VERSION 5.7 ;
  NOWIREEXTENSIONATPIN ON ;
  DIVIDERCHAR "/" ;
  BUSBITCHARS "[]" ;
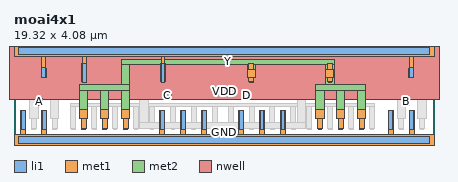
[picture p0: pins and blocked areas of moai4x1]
MACRO moai4x1
  CLASS BLOCK ;
  FOREIGN moai4x1 ;
  ORIGIN 0.000 0.000 ;
  SIZE 19.320 BY 4.080 ;
  PIN A
    ANTENNAGATEAREA 0.441000 ;
    PORT
      LAYER li1 ;
        RECT 0.985 1.660 1.315 1.850 ;
      LAYER met1 ;
        RECT 1.000 1.600 1.300 1.920 ;
    END
  END A
  PIN B
    ANTENNAGATEAREA 0.441000 ;
    PORT
      LAYER li1 ;
        RECT 17.885 1.660 18.215 1.850 ;
      LAYER met1 ;
        RECT 17.900 1.600 18.200 1.920 ;
    END
  END B
  PIN C
    ANTENNAGATEAREA 0.882000 ;
    PORT
      LAYER li1 ;
        RECT 6.905 1.930 7.235 2.120 ;
      LAYER met1 ;
        RECT 6.920 1.870 7.220 2.190 ;
    END
  END C
  PIN D
    ANTENNAGATEAREA 0.882000 ;
    PORT
      LAYER li1 ;
        RECT 10.525 1.930 10.855 2.120 ;
      LAYER met1 ;
        RECT 10.540 1.870 10.840 2.190 ;
    END
  END D
  PIN Y
    ANTENNADIFFAREA 2.150400 ;
    PORT
      LAYER li1 ;
        RECT 10.825 2.660 10.995 3.540 ;
        RECT 14.445 2.660 14.615 3.540 ;
        RECT 3.125 0.490 3.295 1.370 ;
        RECT 4.085 0.490 4.255 1.370 ;
        RECT 5.045 0.490 5.215 1.370 ;
        RECT 13.985 0.490 14.155 1.370 ;
        RECT 14.945 0.490 15.115 1.370 ;
        RECT 15.905 0.490 16.075 1.370 ;
      LAYER met1 ;
        RECT 10.795 3.260 11.025 3.520 ;
        RECT 14.415 3.260 14.645 3.520 ;
        RECT 10.730 2.880 11.090 3.260 ;
        RECT 14.350 2.880 14.710 3.260 ;
        RECT 10.795 2.680 11.025 2.880 ;
        RECT 14.415 2.680 14.645 2.880 ;
        RECT 3.020 1.010 3.400 1.390 ;
        RECT 3.980 1.010 4.360 1.390 ;
        RECT 4.940 1.010 5.320 1.390 ;
        RECT 13.880 1.010 14.260 1.390 ;
        RECT 14.840 1.010 15.220 1.390 ;
        RECT 15.800 1.010 16.180 1.390 ;
        RECT 3.095 0.510 3.325 1.010 ;
        RECT 4.055 0.510 4.285 1.010 ;
        RECT 5.015 0.510 5.245 1.010 ;
        RECT 13.955 0.510 14.185 1.010 ;
        RECT 14.915 0.510 15.145 1.010 ;
        RECT 15.875 0.510 16.105 1.010 ;
      LAYER met2 ;
        RECT 4.940 3.460 14.720 3.720 ;
        RECT 4.940 2.560 5.320 3.460 ;
        RECT 10.720 2.880 11.100 3.460 ;
        RECT 14.340 2.560 14.720 3.460 ;
        RECT 3.020 2.300 5.320 2.560 ;
        RECT 3.020 1.010 3.400 2.300 ;
        RECT 3.980 1.010 4.360 2.300 ;
        RECT 4.940 1.010 5.320 2.300 ;
        RECT 13.880 2.300 16.180 2.560 ;
        RECT 13.880 1.010 14.260 2.300 ;
        RECT 14.840 1.010 15.220 2.300 ;
        RECT 15.800 1.010 16.180 2.300 ;
    END
  END Y
  PIN VDD
    ANTENNADIFFAREA 6.229200 ;
    PORT
      LAYER nwell ;
        RECT -0.230 1.870 19.550 4.410 ;
      LAYER li1 ;
        RECT 0.210 3.915 19.110 4.245 ;
        RECT 1.285 2.870 1.455 3.330 ;
        RECT 3.145 2.660 3.315 3.540 ;
        RECT 6.765 2.660 6.935 3.540 ;
        RECT 18.185 2.870 18.355 3.330 ;
      LAYER met1 ;
        RECT 0.000 3.840 19.320 4.320 ;
        RECT 1.285 3.310 1.455 3.840 ;
        RECT 3.145 3.520 3.315 3.840 ;
        RECT 6.765 3.520 6.935 3.840 ;
        RECT 1.255 2.890 1.485 3.310 ;
        RECT 3.115 2.680 3.345 3.520 ;
        RECT 6.735 2.680 6.965 3.520 ;
        RECT 18.185 3.310 18.355 3.840 ;
        RECT 18.155 2.890 18.385 3.310 ;
    END
  END VDD
  PIN GND
    ANTENNADIFFAREA 8.236800 ;
    PORT
      LAYER li1 ;
        RECT 0.345 0.490 0.515 1.370 ;
        RECT 1.305 0.490 1.475 1.370 ;
        RECT 6.745 0.490 6.915 1.370 ;
        RECT 7.705 0.490 7.875 1.370 ;
        RECT 8.665 0.490 8.835 1.370 ;
        RECT 10.365 0.490 10.535 1.370 ;
        RECT 11.325 0.490 11.495 1.370 ;
        RECT 12.285 0.490 12.455 1.370 ;
        RECT 17.245 0.490 17.415 1.370 ;
        RECT 18.205 0.490 18.375 1.370 ;
        RECT 0.210 -0.165 19.110 0.165 ;
      LAYER met1 ;
        RECT 0.315 0.240 0.545 1.350 ;
        RECT 1.275 0.240 1.505 1.350 ;
        RECT 6.715 0.240 6.945 1.350 ;
        RECT 7.675 0.240 7.905 1.350 ;
        RECT 8.635 0.240 8.865 1.350 ;
        RECT 10.335 0.240 10.565 1.350 ;
        RECT 11.295 0.240 11.525 1.350 ;
        RECT 12.255 0.240 12.485 1.350 ;
        RECT 17.215 0.240 17.445 1.350 ;
        RECT 18.175 0.240 18.405 1.350 ;
        RECT 0.000 -0.240 19.320 0.240 ;
    END
  END GND
  OBS
      LAYER li1 ;
        RECT 0.845 2.870 1.015 3.330 ;
        RECT 3.585 2.660 3.755 3.540 ;
        RECT 7.205 2.660 7.375 3.540 ;
        RECT 10.385 2.660 10.555 3.540 ;
        RECT 14.005 2.660 14.175 3.540 ;
        RECT 17.745 2.870 17.915 3.330 ;
        RECT 3.285 1.930 3.615 2.120 ;
        RECT 14.145 1.930 14.475 2.120 ;
        RECT 0.825 0.490 0.995 1.370 ;
        RECT 1.785 0.490 1.955 1.370 ;
        RECT 2.645 0.490 2.815 1.370 ;
        RECT 3.605 0.490 3.775 1.370 ;
        RECT 4.565 0.490 4.735 1.370 ;
        RECT 5.525 0.490 5.695 1.370 ;
        RECT 6.265 0.490 6.435 1.370 ;
        RECT 7.225 0.490 7.395 1.370 ;
        RECT 8.185 0.490 8.355 1.370 ;
        RECT 9.145 0.490 9.315 1.370 ;
        RECT 9.885 0.490 10.055 1.370 ;
        RECT 10.845 0.490 11.015 1.370 ;
        RECT 11.805 0.490 11.975 1.370 ;
        RECT 12.765 0.490 12.935 1.370 ;
        RECT 13.505 0.490 13.675 1.370 ;
        RECT 14.465 0.490 14.635 1.370 ;
        RECT 15.425 0.490 15.595 1.370 ;
        RECT 16.385 0.490 16.555 1.370 ;
        RECT 17.725 0.490 17.895 1.370 ;
        RECT 18.685 0.490 18.855 1.370 ;
      LAYER met1 ;
        RECT 0.815 3.260 1.045 3.310 ;
        RECT 0.740 2.880 1.100 3.260 ;
        RECT 3.555 3.200 3.785 3.520 ;
        RECT 5.790 3.200 6.170 3.290 ;
        RECT 3.555 3.000 6.170 3.200 ;
        RECT 3.555 2.680 3.785 3.000 ;
        RECT 5.790 2.910 6.170 3.000 ;
        RECT 7.175 3.200 7.405 3.520 ;
        RECT 10.355 3.200 10.585 3.520 ;
        RECT 7.175 3.000 10.585 3.200 ;
        RECT 7.175 2.680 7.405 3.000 ;
        RECT 10.355 2.680 10.585 3.000 ;
        RECT 13.030 3.200 13.410 3.290 ;
        RECT 13.975 3.200 14.205 3.520 ;
        RECT 17.715 3.260 17.945 3.310 ;
        RECT 13.030 3.000 14.205 3.200 ;
        RECT 13.030 2.910 13.410 3.000 ;
        RECT 13.975 2.680 14.205 3.000 ;
        RECT 17.640 2.880 18.000 3.260 ;
        RECT 0.720 2.520 2.060 2.590 ;
        RECT 17.620 2.520 18.960 2.590 ;
        RECT 0.720 2.210 3.600 2.520 ;
        RECT 2.060 2.140 3.600 2.210 ;
        RECT 3.300 1.870 3.600 2.140 ;
        RECT 14.160 2.210 18.960 2.520 ;
        RECT 14.160 2.140 17.740 2.210 ;
        RECT 14.160 1.870 14.460 2.140 ;
        RECT 2.615 1.540 16.585 1.690 ;
        RECT 0.720 1.010 1.100 1.390 ;
        RECT 1.680 1.010 2.060 1.390 ;
        RECT 0.795 0.510 1.025 1.010 ;
        RECT 1.755 0.510 1.985 1.010 ;
        RECT 2.615 0.510 2.845 1.540 ;
        RECT 3.575 0.510 3.805 1.540 ;
        RECT 4.535 0.510 4.765 1.540 ;
        RECT 5.495 0.510 5.725 1.540 ;
        RECT 6.235 0.510 6.465 1.540 ;
        RECT 7.195 0.510 7.425 1.540 ;
        RECT 8.155 0.510 8.385 1.540 ;
        RECT 9.115 0.510 9.345 1.540 ;
        RECT 9.855 0.510 10.085 1.540 ;
        RECT 10.815 0.510 11.045 1.540 ;
        RECT 11.775 0.510 12.005 1.540 ;
        RECT 12.735 0.510 12.965 1.540 ;
        RECT 13.475 0.510 13.705 1.540 ;
        RECT 14.435 0.510 14.665 1.540 ;
        RECT 15.395 0.510 15.625 1.540 ;
        RECT 16.355 0.510 16.585 1.540 ;
        RECT 17.620 1.010 18.000 1.390 ;
        RECT 18.580 1.010 18.960 1.390 ;
        RECT 17.695 0.510 17.925 1.010 ;
        RECT 18.655 0.510 18.885 1.010 ;
      LAYER met2 ;
        RECT 0.720 1.010 1.110 3.260 ;
        RECT 1.680 1.010 2.060 2.590 ;
        RECT 5.790 0.800 6.170 3.230 ;
        RECT 13.030 0.800 13.410 3.230 ;
        RECT 17.620 1.010 18.010 3.260 ;
        RECT 18.580 1.010 18.960 2.590 ;
        RECT 5.790 0.540 13.410 0.800 ;
  END
END moai4x1
END LIBRARY

